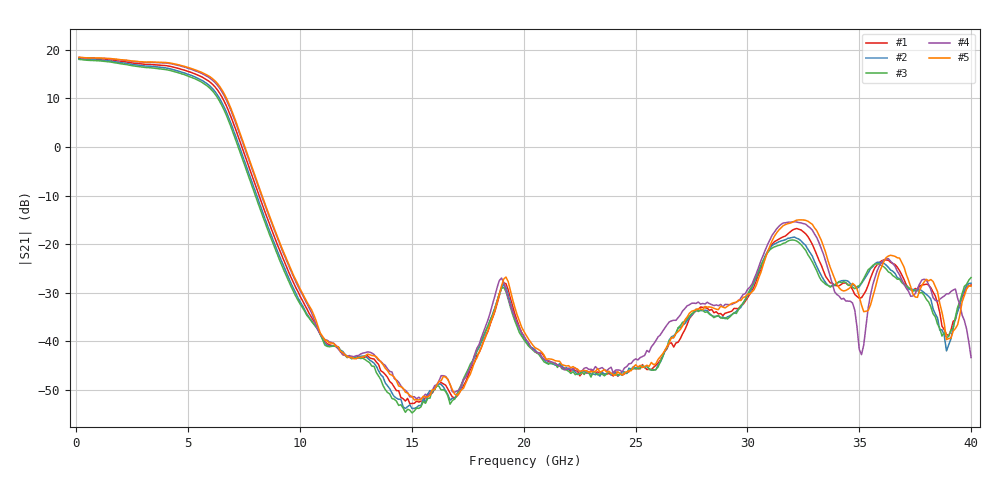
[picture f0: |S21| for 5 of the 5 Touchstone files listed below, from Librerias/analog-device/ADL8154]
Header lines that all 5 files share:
! Analog Devices, Inc."
! Device:	ADL8154ACPZN
! Description:	"10 MHz to 6 GHz, Wideband, Low Noise Amplifier"
! Conditions:	Vdd = 5.0 V
! Product validation unit SN30 soldered down to Evaluation Board as shown on ADL8154-EVALZ User Guide. Board loss de-embedded from S21 magnitude.  All other RF measurements reference to RF coaxial connector.
! Frequency (GHz)	S11_Mag (dB)	S11_Phase (deg)	S21_Mag (dB)	S21_Phase (deg)	S12_Mag (dB)	S12_Phase (deg)	S22_Mag (dB)	S22_Phase (deg)
#  GHZ  S  DB  R 50
Fixed: IDQ = 125 mA, Pin = -25 dBm
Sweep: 110 MHz to 40 GHz
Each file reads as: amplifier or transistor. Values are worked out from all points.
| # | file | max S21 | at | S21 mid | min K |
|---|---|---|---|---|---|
| 1 | ADL8154ACPZN_SParameters_25C.S2p | 18.3 dB | 110 MHz | -39.8 dB at 20.11 GHz | 1.09 |
| 2 | ADL8154ACPZN_SParameters_85C.S2p | 18.1 dB | 110 MHz | -39.9 dB at 20.11 GHz | 1.10 |
| 3 | ADL8154ACPZN_SParameters_125C.S2p | 18.0 dB | 110 MHz | -40.3 dB at 20.11 GHz | 1.11 |
| 4 | ADL8154ACPZN_SParameters_N40C.S2p | 18.4 dB | 110 MHz | -39.7 dB at 20.11 GHz | 1.07 |
| 5 | ADL8154ACPZN_SParameters_N55C.S2p | 18.5 dB | 110 MHz | -38.7 dB at 20.11 GHz | 1.07 |
